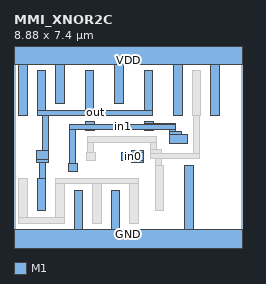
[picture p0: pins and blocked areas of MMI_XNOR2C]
MACRO MMI_XNOR2C
	CLASS CORE ;
	FOREIGN MMI_XNOR2C 0 0 ;
	SIZE 8.88 BY 7.4 ;
	SYMMETRY X Y ;
	SITE CORE1 ;
	PIN out
		DIRECTION output ;
		USE SIGNAL ;
		PORT
			LAYER M1 ;
			RECT 0.9 5.14 1.24 6.67 ;
			LAYER M1 ;
			RECT 2.77 5.14 3.11 6.67 ;
			LAYER M1 ;
			RECT 5.07 5.14 5.41 6.67 ;
			LAYER M1 ;
			RECT 0.9 4.91 5.41 5.14 ;
			LAYER M1 ;
			RECT 1.125 3.555 1.355 4.91 ;
			LAYER M1 ;
			RECT 0.885 3.215 1.355 3.555 ;
			LAYER M1 ;
			RECT 0.885 3.105 1.335 3.215 ;
			LAYER M1 ;
			RECT 1.01 2.49 1.24 3.105 ;
			LAYER M1 ;
			RECT 0.9 1.21 1.24 2.49 ;
		END
		AntennaDiffArea 3.9744 ;
	END out
	PIN in1
		DIRECTION input ;
		USE SIGNAL ;
		PORT
			LAYER M1 ;
			RECT 2.795 4.595 3.135 4.68 ;
			LAYER M1 ;
			RECT 5.095 4.6 5.435 4.68 ;
			LAYER M1 ;
			RECT 5.095 4.595 6.295 4.6 ;
			LAYER M1 ;
			RECT 2.175 4.37 6.295 4.595 ;
			LAYER M1 ;
			RECT 2.175 4.365 5.435 4.37 ;
			LAYER M1 ;
			RECT 2.175 3.07 2.405 4.365 ;
			LAYER M1 ;
			RECT 2.795 4.34 3.135 4.365 ;
			LAYER M1 ;
			RECT 5.095 4.34 5.435 4.365 ;
			LAYER M1 ;
			RECT 6.065 4.295 6.295 4.37 ;
			LAYER M1 ;
			RECT 6.065 4.185 6.515 4.295 ;
			LAYER M1 ;
			RECT 6.065 3.845 6.75 4.185 ;
			LAYER M1 ;
			RECT 2.13 2.73 2.47 3.07 ;
		END
		AntennaGateArea 2.6496 ;
	END in1
	PIN GND
		DIRECTION inout ;
		USE GROUND ;
		PORT
			LAYER M1 ;
			RECT 2.34 0.5 2.68 2.01 ;
			LAYER M1 ;
			RECT 3.78 0.5 4.12 2.01 ;
			LAYER M1 ;
			RECT 6.65 0.5 6.99 2.995 ;
			LAYER M1 ;
			RECT 0 -0.5 8.88 0.5 ;
		END
	END GND
	PIN VDD
		DIRECTION inout ;
		USE POWER ;
		PORT
			LAYER M1 ;
			RECT 0 6.9 8.88 7.9 ;
			LAYER M1 ;
			RECT 0.18 4.91 0.52 6.9 ;
			LAYER M1 ;
			RECT 1.62 5.39 1.96 6.9 ;
			LAYER M1 ;
			RECT 3.92 5.39 4.26 6.9 ;
			LAYER M1 ;
			RECT 6.22 4.91 6.56 6.9 ;
			LAYER M1 ;
			RECT 7.66 4.91 8 6.9 ;
		END
	END VDD
	PIN in0
		DIRECTION input ;
		USE SIGNAL ;
		PORT
			LAYER M1 ;
			RECT 4.585 3.5 5.035 3.555 ;
			LAYER M1 ;
			RECT 4.205 3.16 5.035 3.5 ;
			LAYER M1 ;
			RECT 4.585 3.105 5.035 3.16 ;
		END
		AntennaGateArea 2.6496 ;
	END in0
	OBS
		LAYER M1 ;
		RECT 6.94 4.91 7.28 6.67 ;
		LAYER M1 ;
		RECT 2.865 3.88 5.565 4.11 ;
		LAYER M1 ;
		RECT 2.865 3.5 3.095 3.88 ;
		LAYER M1 ;
		RECT 5.335 3.585 5.565 3.88 ;
		LAYER M1 ;
		RECT 2.815 3.16 3.155 3.5 ;
		LAYER M1 ;
		RECT 5.335 3.465 5.73 3.585 ;
		LAYER M1 ;
		RECT 6.99 3.465 7.22 4.91 ;
		LAYER M1 ;
		RECT 5.335 3.235 7.22 3.465 ;
		LAYER M1 ;
		RECT 5.5 2.995 5.73 3.235 ;
		LAYER M1 ;
		RECT 0.18 0.96 0.52 2.49 ;
		LAYER M1 ;
		RECT 1.62 2.26 4.845 2.49 ;
		LAYER M1 ;
		RECT 1.62 0.96 1.96 2.26 ;
		LAYER M1 ;
		RECT 0.18 0.73 1.96 0.96 ;
		LAYER M1 ;
		RECT 3.06 0.73 3.4 2.26 ;
		LAYER M1 ;
		RECT 4.505 0.73 4.845 2.26 ;
		LAYER M1 ;
		RECT 5.5 1.235 5.84 2.995 ;
	END
END MMI_XNOR2C
